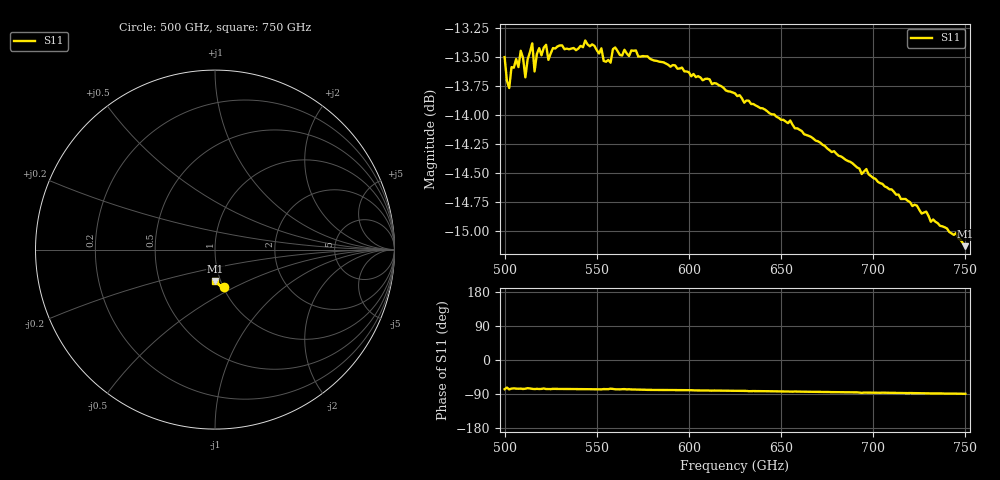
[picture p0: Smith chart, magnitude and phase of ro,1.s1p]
!Created with mwavepy.
! Created with skrf 2.0.1 (http://scikit-rf.org).
# GHz S RI R 50.0
!freq ReS11 ImS11
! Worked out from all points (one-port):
!   201 points, 500 GHz to 750 GHz, reference 50 ohm
!   lowest |S11| = -15.1 dB at 750 GHz (marker M1), VSWR 1.42, Z = 47.3 - j17.1 ohm
!   |S11| at or under -10 dB: start of sweep to end of sweep
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500  0.0477 -0.2059
501.25  0.0613 -0.1971
502.5  0.0443 -0.2001
503.75  0.0523 -0.2026
505  0.0549 -0.2018
507.5  0.0512 -0.2029
508.75  0.0529 -0.206
511.25  0.0508 -0.2008
512.5  0.0572 -0.203
515  0.0514 -0.208
516.25  0.0481 -0.2027
518.75  0.0499 -0.2073
521.25  0.0548 -0.2062
522.5  0.0497 -0.2081
523.75  0.0489 -0.205
531.25  0.0499 -0.2079
543.75  0.0494 -0.2091
552.5  0.0462 -0.2081
553.75  0.0483 -0.2049
557.5  0.0519 -0.2037
558.75  0.0503 -0.207
562.5  0.0461 -0.2067
593.75  0.0382 -0.2054
625  0.0302 -0.2016
656.25  0.0221 -0.1963
687.5  0.0162 -0.1897
718.75  0.0083 -0.183
750  0.0025 -0.1751
